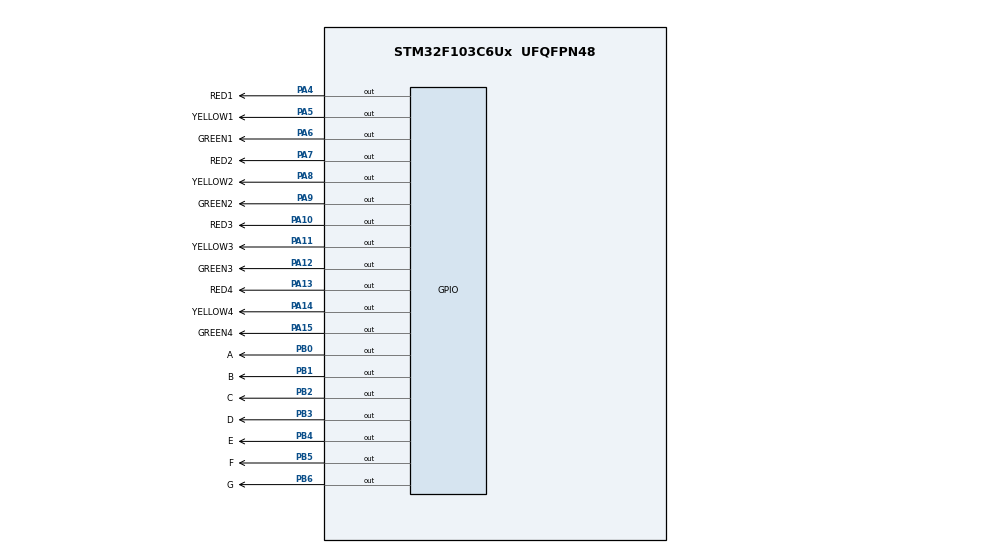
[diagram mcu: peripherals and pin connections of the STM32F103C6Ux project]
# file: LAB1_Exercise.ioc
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Mcu.Family=STM32F1
Mcu.Name=STM32F103C6Ux
Mcu.Package=UFQFPN48
NVIC.PriorityGroup=NVIC_PRIORITYGROUP_4
PA10.GPIO_Label=RED3
PA10.Signal=GPIO_Output
PA11.GPIO_Label=YELLOW3
PA11.Signal=GPIO_Output
PA12.GPIO_Label=GREEN3
PA12.Signal=GPIO_Output
PA13.GPIO_Label=RED4
PA13.Signal=GPIO_Output
PA14.GPIO_Label=YELLOW4
PA14.Signal=GPIO_Output
PA15.GPIO_Label=GREEN4
PA15.Signal=GPIO_Output
PA4.GPIO_Label=RED1
PA4.Signal=GPIO_Output
PA5.GPIO_Label=YELLOW1
PA5.Signal=GPIO_Output
PA6.GPIO_Label=GREEN1
PA6.Signal=GPIO_Output
PA7.GPIO_Label=RED2
PA7.Signal=GPIO_Output
PA8.GPIO_Label=YELLOW2
PA8.Signal=GPIO_Output
PA9.GPIO_Label=GREEN2
PA9.Signal=GPIO_Output
PB0.GPIO_Label=A
PB0.Signal=GPIO_Output
PB1.GPIO_Label=B
PB1.Signal=GPIO_Output
PB2.GPIO_Label=C
PB2.Signal=GPIO_Output
PB3.GPIO_Label=D
PB3.Signal=GPIO_Output
PB4.GPIO_Label=E
PB4.Signal=GPIO_Output
PB5.GPIO_Label=F
PB5.Signal=GPIO_Output
PB6.GPIO_Label=G
PB6.Signal=GPIO_Output
ProjectManager.HeapSize=0x200
ProjectManager.StackSize=0x400
ProjectManager.TargetToolchain=STM32CubeIDE
RCC.APB1Freq_Value=8000000
RCC.APB2Freq_Value=8000000
VP_SYS_VS_ND.Mode=No_Debug
board=custom

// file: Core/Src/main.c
/* USER CODE BEGIN Header */
/**
  ******************************************************************************
  * @file           : main.c
  * @brief          : Main program body
  ******************************************************************************
  * @attention
  *
  * <h2><center>&copy; Copyright (c) 2023 STMicroelectronics.
  * All rights reserved.</center></h2>
  *
  * This software component is licensed by ST under BSD 3-Clause license,
  * the "License"; You may not use this file except in compliance with the
  * License. You may obtain a copy of the License at:
  *                        opensource.org/licenses/BSD-3-Clause
  *
  ******************************************************************************
  */
/* USER CODE END Header */
#include "main.h"

void SystemClock_Config(void);
static void MX_GPIO_Init(void);

void clearAllClock(){
	HAL_GPIO_WritePin(LED0_GPIO_Port, LED0_Pin, GPIO_PIN_SET);
	HAL_GPIO_WritePin(LED1_GPIO_Port, LED1_Pin, GPIO_PIN_SET);
	HAL_GPIO_WritePin(LED2_GPIO_Port, LED2_Pin, GPIO_PIN_SET);
	HAL_GPIO_WritePin(LED3_GPIO_Port, LED3_Pin, GPIO_PIN_SET);
	HAL_GPIO_WritePin(LED4_GPIO_Port, LED4_Pin, GPIO_PIN_SET);
	HAL_GPIO_WritePin(LED5_GPIO_Port, LED5_Pin, GPIO_PIN_SET);
	HAL_GPIO_WritePin(LED6_GPIO_Port, LED6_Pin, GPIO_PIN_SET);
	HAL_GPIO_WritePin(LED7_GPIO_Port, LED7_Pin, GPIO_PIN_SET);
	HAL_GPIO_WritePin(LED8_GPIO_Port, LED8_Pin, GPIO_PIN_SET);
	HAL_GPIO_WritePin(LED9_GPIO_Port, LED9_Pin, GPIO_PIN_SET);
	HAL_GPIO_WritePin(LED10_GPIO_Port, LED10_Pin, GPIO_PIN_SET);
	HAL_GPIO_WritePin(LED11_GPIO_Port, LED11_Pin, GPIO_PIN_SET);
}
void setNumberOffClock(int num){

	if (num == 0){
		HAL_GPIO_WritePin(LED0_GPIO_Port, LED0_Pin, GPIO_PIN_RESET);
	}
	else if (num == 1){
		HAL_GPIO_WritePin(LED1_GPIO_Port, LED1_Pin, GPIO_PIN_RESET);
	}
	else if (num == 2){
		HAL_GPIO_WritePin(LED2_GPIO_Port, LED2_Pin, GPIO_PIN_RESET);
	}
	else if (num == 3){
		HAL_GPIO_WritePin(LED3_GPIO_Port, LED3_Pin, GPIO_PIN_RESET);
	}
	else if (num == 4){
		HAL_GPIO_WritePin(LED4_GPIO_Port, LED4_Pin, GPIO_PIN_RESET);
	}
	else if (num == 5){
		HAL_GPIO_WritePin(LED5_GPIO_Port, LED5_Pin, GPIO_PIN_RESET);
	}
	else if (num == 6){
		HAL_GPIO_WritePin(LED6_GPIO_Port, LED6_Pin, GPIO_PIN_RESET);
	}
	else if (num == 7){
		HAL_GPIO_WritePin(LED7_GPIO_Port, LED7_Pin, GPIO_PIN_RESET);
	}
	else if (num == 8){
		HAL_GPIO_WritePin(LED8_GPIO_Port, LED8_Pin, GPIO_PIN_RESET);
	}
	else if (num == 9){
		HAL_GPIO_WritePin(LED9_GPIO_Port, LED9_Pin, GPIO_PIN_RESET);
	}
	else if (num == 10){
		HAL_GPIO_WritePin(LED10_GPIO_Port, LED10_Pin, GPIO_PIN_RESET);
	}
	else {
		HAL_GPIO_WritePin(LED11_GPIO_Port, LED11_Pin, GPIO_PIN_RESET);
	}

}
int main(void)
{

  /* MCU Configuration--------------------------------------------------------*/

  /* Reset of all peripherals, Initializes the Flash interface and the Systick. */
  HAL_Init();

  /* Configure the system clock */
  SystemClock_Config();

  /* Initialize all configured peripherals */
  MX_GPIO_Init();

  /* Infinite loop */
  /* USER CODE BEGIN WHILE */
  int num = 0;
    while (1)
    {
  	  if (num >= 12){
  		clearAllClock();
  		num = 0;
  	  }
  	  setNumberOffClock(num++);
  	  HAL_Delay(1000);
    /* USER CODE END WHILE */

  }
}

void SystemClock_Config(void)
{
  RCC_OscInitTypeDef RCC_OscInitStruct = {0};
  RCC_ClkInitTypeDef RCC_ClkInitStruct = {0};

  /** Initializes the RCC Oscillators according to the specified parameters
  * in the RCC_OscInitTypeDef structure.
  */
  RCC_OscInitStruct.OscillatorType = RCC_OSCILLATORTYPE_HSI;
  RCC_OscInitStruct.HSIState = RCC_HSI_ON;
  RCC_OscInitStruct.HSICalibrationValue = RCC_HSICALIBRATION_DEFAULT;
  RCC_OscInitStruct.PLL.PLLState = RCC_PLL_NONE;
  if (HAL_RCC_OscConfig(&RCC_OscInitStruct) != HAL_OK)
  {
    Error_Handler();
  }
  /** Initializes the CPU, AHB and APB buses clocks
  */
  RCC_ClkInitStruct.ClockType = RCC_CLOCKTYPE_HCLK|RCC_CLOCKTYPE_SYSCLK
                              |RCC_CLOCKTYPE_PCLK1|RCC_CLOCKTYPE_PCLK2;
  RCC_ClkInitStruct.SYSCLKSource = RCC_SYSCLKSOURCE_HSI;
  RCC_ClkInitStruct.AHBCLKDivider = RCC_SYSCLK_DIV1;
  RCC_ClkInitStruct.APB1CLKDivider = RCC_HCLK_DIV1;
  RCC_ClkInitStruct.APB2CLKDivider = RCC_HCLK_DIV1;

  if (HAL_RCC_ClockConfig(&RCC_ClkInitStruct, FLASH_LATENCY_0) != HAL_OK)
  {
    Error_Handler();
  }
}

static void MX_GPIO_Init(void)
{
  GPIO_InitTypeDef GPIO_InitStruct = {0};

  /* GPIO Ports Clock Enable */
  __HAL_RCC_GPIOA_CLK_ENABLE();

  /*Configure GPIO pin Output Level */
  HAL_GPIO_WritePin(GPIOA, LED0_Pin|LED1_Pin|LED2_Pin|LED3_Pin
                          |LED4_Pin|LED5_Pin|LED6_Pin|LED7_Pin
                          |LED8_Pin|LED9_Pin|LED10_Pin|LED11_Pin, GPIO_PIN_RESET);

  /*Configure GPIO pins : LED0_Pin LED1_Pin LED2_Pin LED3_Pin
                           LED4_Pin LED5_Pin LED6_Pin LED7_Pin
                           LED8_Pin LED9_Pin LED10_Pin LED11_Pin */
  GPIO_InitStruct.Pin = LED0_Pin|LED1_Pin|LED2_Pin|LED3_Pin
                          |LED4_Pin|LED5_Pin|LED6_Pin|LED7_Pin
                          |LED8_Pin|LED9_Pin|LED10_Pin|LED11_Pin;
  GPIO_InitStruct.Mode = GPIO_MODE_OUTPUT_PP;
  GPIO_InitStruct.Pull = GPIO_NOPULL;
  GPIO_InitStruct.Speed = GPIO_SPEED_FREQ_LOW;
  HAL_GPIO_Init(GPIOA, &GPIO_InitStruct);

}

void Error_Handler(void)
{
  __disable_irq();
  while (1)
  {
  }
}

/************************ (C) COPYRIGHT STMicroelectronics *****END OF FILE****/
